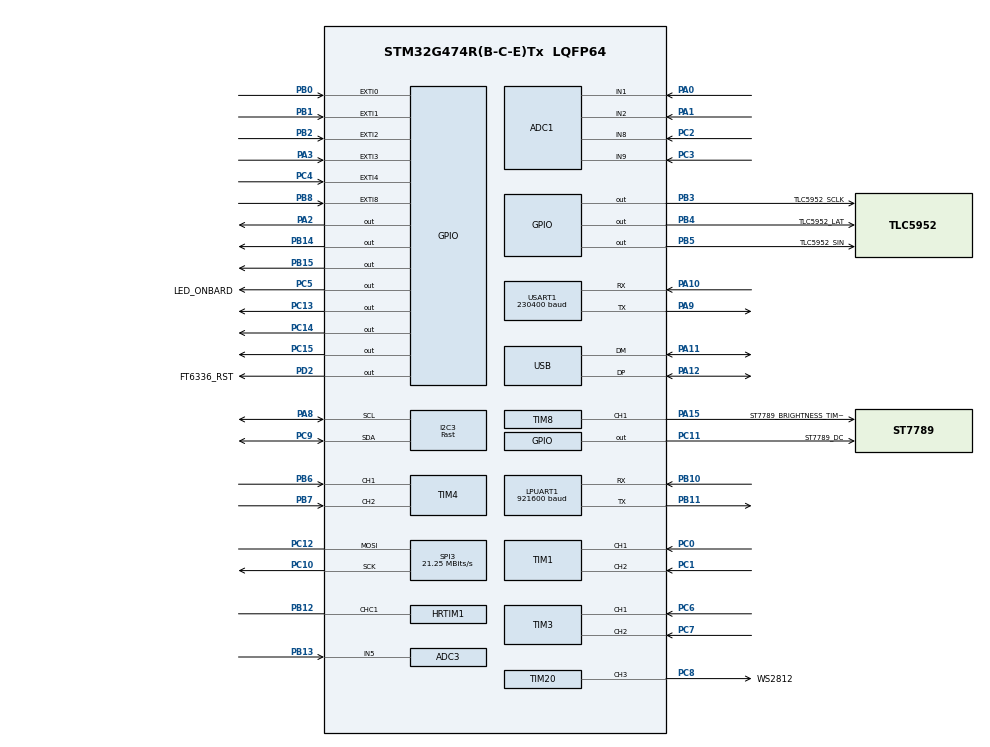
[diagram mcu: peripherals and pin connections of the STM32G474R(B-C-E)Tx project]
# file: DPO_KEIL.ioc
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ADC1.Channel-0\#ChannelRegularConversion=ADC_CHANNEL_8
ADC1.Channel-1\#ChannelRegularConversion=ADC_CHANNEL_9
ADC1.Channel-2\#ChannelRegularConversion=ADC_CHANNEL_1
ADC1.Channel-3\#ChannelRegularConversion=ADC_CHANNEL_2
ADC1.ClockPrescaler=ADC_CLOCK_ASYNC_DIV1
ADC1.ContinuousConvMode=ENABLE
ADC1.DMAContinuousRequests=ENABLE
ADC1.EOCSelection=ADC_EOC_SEQ_CONV
ADC1.ExternalTrigConv=ADC_EXTERNALTRIG_T6_TRGO
ADC1.NbrOfConversion=4
ADC1.NbrOfConversionFlag=1
ADC1.OffsetNumber-0\#ChannelRegularConversion=ADC_OFFSET_NONE
ADC1.OffsetNumber-1\#ChannelRegularConversion=ADC_OFFSET_NONE
ADC1.OffsetNumber-2\#ChannelRegularConversion=ADC_OFFSET_NONE
ADC1.OffsetNumber-3\#ChannelRegularConversion=ADC_OFFSET_NONE
ADC1.Rank-0\#ChannelRegularConversion=1
ADC1.Rank-1\#ChannelRegularConversion=2
ADC1.Rank-2\#ChannelRegularConversion=3
ADC1.Rank-3\#ChannelRegularConversion=4
ADC1.SamplingTime-0\#ChannelRegularConversion=ADC_SAMPLETIME_2CYCLES_5
ADC1.SamplingTime-1\#ChannelRegularConversion=ADC_SAMPLETIME_2CYCLES_5
ADC1.SamplingTime-2\#ChannelRegularConversion=ADC_SAMPLETIME_2CYCLES_5
ADC1.SamplingTime-3\#ChannelRegularConversion=ADC_SAMPLETIME_2CYCLES_5
ADC1.master=1
ADC3.Channel-0\#ChannelRegularConversion=ADC_CHANNEL_5
ADC3.ClockPrescaler=ADC_CLOCK_ASYNC_DIV1
ADC3.NbrOfConversionFlag=1
ADC3.OffsetNumber-0\#ChannelRegularConversion=ADC_OFFSET_NONE
ADC3.Rank-0\#ChannelRegularConversion=1
ADC3.SamplingTime-0\#ChannelRegularConversion=ADC_SAMPLETIME_2CYCLES_5
ADC3.master=1
Dma.ADC1.8.Direction=DMA_PERIPH_TO_MEMORY
Dma.ADC1.8.EventEnable=DISABLE
Dma.ADC1.8.Instance=DMA2_Channel1
Dma.ADC1.8.MemDataAlignment=DMA_MDATAALIGN_WORD
Dma.ADC1.8.MemInc=DMA_MINC_ENABLE
Dma.ADC1.8.Mode=DMA_CIRCULAR
Dma.ADC1.8.PeriphDataAlignment=DMA_PDATAALIGN_WORD
Dma.ADC1.8.PeriphInc=DMA_PINC_DISABLE
Dma.ADC1.8.Polarity=HAL_DMAMUX_REQ_GEN_RISING
Dma.ADC1.8.Priority=DMA_PRIORITY_LOW
Dma.ADC1.8.RequestNumber=1
Dma.ADC1.8.SignalID=NONE
Dma.ADC1.8.SyncEnable=DISABLE
Dma.ADC1.8.SyncPolarity=HAL_DMAMUX_SYNC_NO_EVENT
Dma.ADC1.8.SyncRequestNumber=1
Dma.ADC1.8.SyncSignalID=NONE
Dma.I2C3_RX.6.Direction=DMA_PERIPH_TO_MEMORY
Dma.I2C3_RX.6.EventEnable=DISABLE
Dma.I2C3_RX.6.Instance=DMA1_Channel7
Dma.I2C3_RX.6.MemDataAlignment=DMA_MDATAALIGN_BYTE
Dma.I2C3_RX.6.MemInc=DMA_MINC_ENABLE
Dma.I2C3_RX.6.Mode=DMA_NORMAL
Dma.I2C3_RX.6.PeriphDataAlignment=DMA_PDATAALIGN_BYTE
Dma.I2C3_RX.6.PeriphInc=DMA_PINC_DISABLE
Dma.I2C3_RX.6.Polarity=HAL_DMAMUX_REQ_GEN_RISING
Dma.I2C3_RX.6.Priority=DMA_PRIORITY_LOW
Dma.I2C3_RX.6.RequestNumber=1
Dma.I2C3_RX.6.SignalID=NONE
Dma.I2C3_RX.6.SyncEnable=DISABLE
Dma.I2C3_RX.6.SyncPolarity=HAL_DMAMUX_SYNC_NO_EVENT
Dma.I2C3_RX.6.SyncRequestNumber=1
Dma.I2C3_RX.6.SyncSignalID=NONE
Dma.I2C3_TX.5.Direction=DMA_MEMORY_TO_PERIPH
Dma.I2C3_TX.5.EventEnable=DISABLE
Dma.I2C3_TX.5.Instance=DMA1_Channel6
Dma.I2C3_TX.5.MemDataAlignment=DMA_MDATAALIGN_BYTE
Dma.I2C3_TX.5.MemInc=DMA_MINC_ENABLE
Dma.I2C3_TX.5.Mode=DMA_NORMAL
Dma.I2C3_TX.5.PeriphDataAlignment=DMA_PDATAALIGN_BYTE
Dma.I2C3_TX.5.PeriphInc=DMA_PINC_DISABLE
Dma.I2C3_TX.5.Polarity=HAL_DMAMUX_REQ_GEN_RISING
Dma.I2C3_TX.5.Priority=DMA_PRIORITY_LOW
Dma.I2C3_TX.5.RequestNumber=1
Dma.I2C3_TX.5.SignalID=NONE
Dma.I2C3_TX.5.SyncEnable=DISABLE
Dma.I2C3_TX.5.SyncPolarity=HAL_DMAMUX_SYNC_NO_EVENT
Dma.I2C3_TX.5.SyncRequestNumber=1
Dma.I2C3_TX.5.SyncSignalID=NONE
Dma.LPUART1_RX.3.Direction=DMA_PERIPH_TO_MEMORY
Dma.LPUART1_RX.3.EventEnable=DISABLE
Dma.LPUART1_RX.3.Instance=DMA1_Channel4
Dma.LPUART1_RX.3.MemDataAlignment=DMA_MDATAALIGN_BYTE
Dma.LPUART1_RX.3.MemInc=DMA_MINC_ENABLE
Dma.LPUART1_RX.3.Mode=DMA_NORMAL
Dma.LPUART1_RX.3.PeriphDataAlignment=DMA_PDATAALIGN_BYTE
Dma.LPUART1_RX.3.PeriphInc=DMA_PINC_DISABLE
Dma.LPUART1_RX.3.Polarity=HAL_DMAMUX_REQ_GEN_RISING
Dma.LPUART1_RX.3.Priority=DMA_PRIORITY_LOW
Dma.LPUART1_RX.3.RequestNumber=1
Dma.LPUART1_RX.3.SignalID=NONE
Dma.LPUART1_RX.3.SyncEnable=DISABLE
Dma.LPUART1_RX.3.SyncPolarity=HAL_DMAMUX_SYNC_NO_EVENT
Dma.LPUART1_RX.3.SyncRequestNumber=1
Dma.LPUART1_RX.3.SyncSignalID=NONE
Dma.LPUART1_TX.4.Direction=DMA_MEMORY_TO_PERIPH
Dma.LPUART1_TX.4.EventEnable=DISABLE
Dma.LPUART1_TX.4.Instance=DMA1_Channel5
Dma.LPUART1_TX.4.MemDataAlignment=DMA_MDATAALIGN_BYTE
Dma.LPUART1_TX.4.MemInc=DMA_MINC_ENABLE
Dma.LPUART1_TX.4.Mode=DMA_NORMAL
Dma.LPUART1_TX.4.PeriphDataAlignment=DMA_PDATAALIGN_BYTE
Dma.LPUART1_TX.4.PeriphInc=DMA_PINC_DISABLE
Dma.LPUART1_TX.4.Polarity=HAL_DMAMUX_REQ_GEN_RISING
Dma.LPUART1_TX.4.Priority=DMA_PRIORITY_LOW
Dma.LPUART1_TX.4.RequestNumber=1
Dma.LPUART1_TX.4.SignalID=NONE
Dma.LPUART1_TX.4.SyncEnable=DISABLE
Dma.LPUART1_TX.4.SyncPolarity=HAL_DMAMUX_SYNC_NO_EVENT
Dma.LPUART1_TX.4.SyncRequestNumber=1
Dma.LPUART1_TX.4.SyncSignalID=NONE
Dma.Request0=TIM20_CH3
Dma.Request1=USART1_RX
Dma.Request2=USART1_TX
Dma.Request3=LPUART1_RX
Dma.Request4=LPUART1_TX
Dma.Request5=I2C3_TX
Dma.Request6=I2C3_RX
Dma.Request7=SPI3_TX
Dma.Request8=ADC1
Dma.SPI3_TX.7.Direction=DMA_MEMORY_TO_PERIPH
Dma.SPI3_TX.7.EventEnable=DISABLE
Dma.SPI3_TX.7.Instance=DMA1_Channel8
Dma.SPI3_TX.7.MemDataAlignment=DMA_MDATAALIGN_BYTE
Dma.SPI3_TX.7.MemInc=DMA_MINC_ENABLE
Dma.SPI3_TX.7.Mode=DMA_NORMAL
Dma.SPI3_TX.7.PeriphDataAlignment=DMA_PDATAALIGN_BYTE
Dma.SPI3_TX.7.PeriphInc=DMA_PINC_DISABLE
Dma.SPI3_TX.7.Polarity=HAL_DMAMUX_REQ_GEN_RISING
Dma.SPI3_TX.7.Priority=DMA_PRIORITY_LOW
Dma.SPI3_TX.7.RequestNumber=1
Dma.SPI3_TX.7.SignalID=NONE
Dma.SPI3_TX.7.SyncEnable=DISABLE
Dma.SPI3_TX.7.SyncPolarity=HAL_DMAMUX_SYNC_NO_EVENT
Dma.SPI3_TX.7.SyncRequestNumber=1
Dma.SPI3_TX.7.SyncSignalID=NONE
Dma.TIM20_CH3.0.Direction=DMA_MEMORY_TO_PERIPH
Dma.TIM20_CH3.0.EventEnable=DISABLE
Dma.TIM20_CH3.0.Instance=DMA1_Channel1
Dma.TIM20_CH3.0.MemDataAlignment=DMA_MDATAALIGN_HALFWORD
Dma.TIM20_CH3.0.MemInc=DMA_MINC_ENABLE
Dma.TIM20_CH3.0.Mode=DMA_NORMAL
Dma.TIM20_CH3.0.PeriphDataAlignment=DMA_PDATAALIGN_HALFWORD
Dma.TIM20_CH3.0.PeriphInc=DMA_PINC_DISABLE
Dma.TIM20_CH3.0.Polarity=HAL_DMAMUX_REQ_GEN_RISING
Dma.TIM20_CH3.0.Priority=DMA_PRIORITY_LOW
Dma.TIM20_CH3.0.RequestNumber=1
Dma.TIM20_CH3.0.SignalID=NONE
Dma.TIM20_CH3.0.SyncEnable=DISABLE
Dma.TIM20_CH3.0.SyncPolarity=HAL_DMAMUX_SYNC_NO_EVENT
Dma.TIM20_CH3.0.SyncRequestNumber=1
Dma.TIM20_CH3.0.SyncSignalID=NONE
Dma.USART1_RX.1.Direction=DMA_PERIPH_TO_MEMORY
Dma.USART1_RX.1.EventEnable=DISABLE
Dma.USART1_RX.1.Instance=DMA1_Channel2
Dma.USART1_RX.1.MemDataAlignment=DMA_MDATAALIGN_BYTE
Dma.USART1_RX.1.MemInc=DMA_MINC_ENABLE
Dma.USART1_RX.1.Mode=DMA_NORMAL
Dma.USART1_RX.1.PeriphDataAlignment=DMA_PDATAALIGN_BYTE
Dma.USART1_RX.1.PeriphInc=DMA_PINC_DISABLE
Dma.USART1_RX.1.Polarity=HAL_DMAMUX_REQ_GEN_RISING
Dma.USART1_RX.1.Priority=DMA_PRIORITY_LOW
Dma.USART1_RX.1.RequestNumber=1
Dma.USART1_RX.1.SignalID=NONE
Dma.USART1_RX.1.SyncEnable=DISABLE
Dma.USART1_RX.1.SyncPolarity=HAL_DMAMUX_SYNC_NO_EVENT
Dma.USART1_RX.1.SyncRequestNumber=1
Dma.USART1_RX.1.SyncSignalID=NONE
Dma.USART1_TX.2.Direction=DMA_MEMORY_TO_PERIPH
Dma.USART1_TX.2.EventEnable=DISABLE
Dma.USART1_TX.2.Instance=DMA1_Channel3
Dma.USART1_TX.2.MemDataAlignment=DMA_MDATAALIGN_BYTE
Dma.USART1_TX.2.MemInc=DMA_MINC_ENABLE
Dma.USART1_TX.2.Mode=DMA_NORMAL
Dma.USART1_TX.2.PeriphDataAlignment=DMA_PDATAALIGN_BYTE
Dma.USART1_TX.2.PeriphInc=DMA_PINC_DISABLE
Dma.USART1_TX.2.Polarity=HAL_DMAMUX_REQ_GEN_RISING
Dma.USART1_TX.2.Priority=DMA_PRIORITY_LOW
Dma.USART1_TX.2.RequestNumber=1
Dma.USART1_TX.2.SignalID=NONE
Dma.USART1_TX.2.SyncEnable=DISABLE
Dma.USART1_TX.2.SyncPolarity=HAL_DMAMUX_SYNC_NO_EVENT
Dma.USART1_TX.2.SyncRequestNumber=1
Dma.USART1_TX.2.SyncSignalID=NONE
HRTIM1.Configuration_TC=Simple
HRTIM1.PWMChannel_TC1=HRTIM_OUTPUT_TC1
HRTIM1.PWMPulse_TC1=0x30
HRTIM1.Periode_TC=0x60
HRTIM1.RepetitionCounter-Output_TC1=0
I2C3.I2C_Speed_Mode=I2C_Fast
I2C3.Timing=0x40621236
LPUART1.BaudRate=921600
Mcu.Family=STM32G4
Mcu.Name=STM32G474R(B-C-E)Tx
Mcu.Package=LQFP64
NVIC.DMA1_Channel1_IRQn=true\:0\:0\:false\:false\:true\:false\:true\:true
NVIC.DMA1_Channel2_IRQn=true\:0\:0\:false\:false\:true\:false\:true\:true
NVIC.DMA1_Channel3_IRQn=true\:0\:0\:false\:false\:true\:false\:true\:true
NVIC.DMA1_Channel4_IRQn=true\:0\:0\:false\:false\:true\:false\:true\:true
NVIC.DMA1_Channel5_IRQn=true\:0\:0\:false\:false\:true\:false\:true\:true
NVIC.DMA1_Channel6_IRQn=true\:0\:0\:false\:false\:true\:false\:true\:true
NVIC.DMA1_Channel7_IRQn=true\:0\:0\:false\:false\:true\:false\:true\:true
NVIC.DMA1_Channel8_IRQn=true\:0\:0\:false\:false\:true\:false\:true\:true
NVIC.DMA2_Channel1_IRQn=true\:0\:0\:false\:false\:true\:false\:true\:true
NVIC.LPUART1_IRQn=true\:0\:0\:false\:false\:true\:true\:true\:true
NVIC.PriorityGroup=NVIC_PRIORITYGROUP_4
NVIC.USART1_IRQn=true\:0\:0\:false\:false\:true\:true\:true\:true
NVIC.USB_LP_IRQn=true\:0\:0\:false\:false\:true\:false\:true\:true
PA0.Mode=IN1-Single-Ended
PA0.Signal=ADC1_IN1
PA1.Mode=IN2-Single-Ended
PA1.Signal=ADC1_IN2
PA10.Mode=Asynchronous
PA10.Signal=USART1_RX
PA11.Mode=Device
PA11.Signal=USB_DM
PA12.Mode=Device
PA12.Signal=USB_DP
PA13.Mode=Serial_Wire
PA13.Signal=SYS_JTMS-SWDIO
PA14.Mode=Serial_Wire
PA14.Signal=SYS_JTCK-SWCLK
PA15.GPIO_Label=ST7789_BRIGHTNESS_TIM8_1
PA15.Signal=S_TIM8_CH1
PA2.Signal=GPIO_Output
PA3.Signal=GPXTI3
PA4.Signal=COMP_DAC11_group
PA5.Signal=COMP_DAC12_group
PA6.Signal=COMP_DAC21_group
PA7.Signal=ADC2_IN4
PA8.Mode=I2C
PA8.Signal=I2C3_SCL
PA9.Mode=Asynchronous
PA9.Signal=USART1_TX
PB0.Signal=GPXTI0
PB1.Signal=GPXTI1
PB10.Mode=Asynchronous
PB10.Signal=LPUART1_RX
PB11.Mode=Asynchronous
PB11.Signal=LPUART1_TX
PB12.Mode=Output_TC1
PB12.Signal=HRTIM1_CHC1
PB13.Mode=IN5-Single-Ended
PB13.Signal=ADC3_IN5
PB14.Signal=GPIO_Output
PB15.Signal=GPIO_Output
PB2.Signal=GPXTI2
PB3.GPIO_Label=TLC5952_SCLK
PB3.Signal=GPIO_Output
PB4.GPIO_Label=TLC5952_LAT
PB4.Signal=GPIO_Output
PB5.GPIO_Label=TLC5952_SIN
PB5.Signal=GPIO_Output
PB6.Signal=S_TIM4_CH1
PB7.Signal=S_TIM4_CH2
PB8-BOOT0.Signal=GPXTI8
PB9.GPIO_Label=BEEP_TIM8_3
PB9.Signal=S_TIM8_CH3
PC0.Signal=S_TIM1_CH1
PC1.Signal=S_TIM1_CH2
PC10.Mode=Simplex_Bidirectional_Master
PC10.Signal=SPI3_SCK
PC11.GPIO_Label=ST7789_DC
PC11.Signal=GPIO_Output
PC12.Mode=Simplex_Bidirectional_Master
PC12.Signal=SPI3_MOSI
PC13.Signal=GPIO_Output
PC14-OSC32_IN.Signal=GPIO_Output
PC15-OSC32_OUT.Signal=GPIO_Output
PC2.Mode=IN8-Single-Ended
PC2.Signal=ADC1_IN8
PC3.Mode=IN9-Single-Ended
PC3.Signal=ADC1_IN9
PC4.Signal=GPXTI4
PC5.GPIO_Label=LED_ONBARD
PC5.Signal=GPIO_Output
PC6.Signal=S_TIM3_CH1
PC7.Signal=S_TIM3_CH2
PC8.GPIO_Label=WS2812
PC8.Signal=S_TIM20_CH3
PC9.Mode=I2C
PC9.Signal=I2C3_SDA
PD2.GPIO_Label=FT6336_RST
PD2.Signal=GPIO_Output
PF0-OSC_IN.Mode=HSE-External-Oscillator
PF0-OSC_IN.Signal=RCC_OSC_IN
PF1-OSC_OUT.Mode=HSE-External-Oscillator
PF1-OSC_OUT.Signal=RCC_OSC_OUT
ProjectManager.HeapSize=0x200
ProjectManager.StackSize=0x400
ProjectManager.TargetToolchain=MDK-ARM V5.32
RCC.ADC12CLockSelection=RCC_ADC12CLKSOURCE_PLL
RCC.ADC12Freq_Value=56666666.666666664
RCC.ADC345CLockSelection=RCC_ADC345CLKSOURCE_PLL
RCC.ADC345Freq_Value=56666666.666666664
RCC.AHBFreq_Value=170000000
RCC.APB1Freq_Value=170000000
RCC.APB1TimFreq_Value=170000000
RCC.APB2Freq_Value=170000000
RCC.APB2TimFreq_Value=170000000
RCC.CK48CLockSelection=RCC_USBCLKSOURCE_HSI48
RCC.CortexFreq_Value=170000000
RCC.EXTERNAL_CLOCK_VALUE=12288000
RCC.HCLKFreq_Value=170000000
RCC.HSE_VALUE=16000000
RCC.HSI48_VALUE=48000000
RCC.HSI_VALUE=16000000
RCC.LSE_VALUE=32768
RCC.PLLM=RCC_PLLM_DIV4
RCC.PLLN=85
RCC.PLLP=RCC_PLLP_DIV6
RCC.PLLSourceVirtual=RCC_PLLSOURCE_HSE
RCC.SYSCLKFreq_VALUE=170000000
RCC.SYSCLKSource=RCC_SYSCLKSOURCE_PLLCLK
RCC.USBFreq_Value=48000000
RCC.VCOOutputFreq_Value=340000000
SH.COMP_DAC11_group.0=DAC1_OUT1
SH.COMP_DAC12_group.0=DAC1_OUT2
SH.COMP_DAC21_group.0=DAC2_OUT1
SH.S_TIM1_CH1.0=TIM1_CH1,Encoder_Interface
SH.S_TIM1_CH2.0=TIM1_CH2,Encoder_Interface
SH.S_TIM20_CH3.0=TIM20_CH3,PWM Generation3 CH3
SH.S_TIM3_CH1.0=TIM3_CH1,Encoder_Interface
SH.S_TIM3_CH2.0=TIM3_CH2,Encoder_Interface
SH.S_TIM4_CH1.0=TIM4_CH1,Encoder_Interface
SH.S_TIM4_CH2.0=TIM4_CH2,Encoder_Interface
SH.S_TIM8_CH1.0=TIM8_CH1,PWM Generation1 CH1
SH.S_TIM8_CH3.0=TIM8_CH3
SPI3.BaudRatePrescaler=SPI_BAUDRATEPRESCALER_8
SPI3.CLKPolarity=SPI_POLARITY_HIGH
SPI3.CalculateBaudRate=21.25 MBits/s
SPI3.DataSize=SPI_DATASIZE_8BIT
SPI3.Direction=SPI_DIRECTION_1LINE
SPI3.Mode=SPI_MODE_MASTER
SPI3.VirtualType=VM_MASTER
TIM20.Channel-PWM\ Generation3\ CH3=TIM_CHANNEL_3
TIM20.PeriodNoDither=180-1
TIM6.PeriodNoDither=180
TIM6.TIM_MasterOutputTrigger=TIM_TRGO_UPDATE
TIM8.Channel-PWM\ Generation1\ CH1=TIM_CHANNEL_1
TIM8.PeriodNoDither=1000-1
TIM8.Prescaler=180-1
TIM8.PulseNoDither_1=500
USART1.BaudRate=230400
USART1.VirtualMode-Asynchronous=VM_ASYNC
USB_DEVICE.CLASS_NAME_FS=CDC
USB_DEVICE.VirtualMode=Cdc
USB_DEVICE.VirtualModeFS=Cdc_FS
VP_SYS_VS_DBSignals.Mode=DisableDeadBatterySignals
VP_TIM6_VS_ClockSourceINT.Mode=Enable_Timer
VP_TIM8_VS_ClockSourceINT.Mode=Internal
VP_USB_DEVICE_VS_USB_DEVICE_CDC_FS.Mode=CDC_FS
board=custom

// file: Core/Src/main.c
/* USER CODE BEGIN Header */
/**
  ******************************************************************************
  * @file           : main.c
  * @brief          : Main program body
  ******************************************************************************
  * @attention
  *
  * Copyright (c) 2025 STMicroelectronics.
  * All rights reserved.
  *
  * This software is licensed under terms that can be found in the LICENSE file
  * in the root directory of this software component.
  * If no LICENSE file comes with this software, it is provided AS-IS.
  *
  ******************************************************************************
  */
/* USER CODE END Header */
#include "main.h"
#include "usb_device.h"

/* USER CODE BEGIN Includes */

#include "usbd_cdc_if.h"

#include "MyLib.h"

#include "ft6336.h"

#include "st7789.h"

#include "TLC5952.h"

#include "ws2812.h"

#include "aht20.h"

#include "Views.h"

#include "mpu6050.h"

/* USER CODE END Includes */

ADC_HandleTypeDef hadc1;
ADC_HandleTypeDef hadc3;
DMA_HandleTypeDef hdma_adc1;

HRTIM_HandleTypeDef hhrtim1;

I2C_HandleTypeDef hi2c3;
DMA_HandleTypeDef hdma_i2c3_tx;
DMA_HandleTypeDef hdma_i2c3_rx;

UART_HandleTypeDef hlpuart1;
UART_HandleTypeDef huart1;
DMA_HandleTypeDef hdma_lpuart1_rx;
DMA_HandleTypeDef hdma_lpuart1_tx;
DMA_HandleTypeDef hdma_usart1_rx;
DMA_HandleTypeDef hdma_usart1_tx;

SPI_HandleTypeDef hspi3;
DMA_HandleTypeDef hdma_spi3_tx;

TIM_HandleTypeDef htim1;
TIM_HandleTypeDef htim3;
TIM_HandleTypeDef htim4;
TIM_HandleTypeDef htim6;
TIM_HandleTypeDef htim8;
TIM_HandleTypeDef htim20;
DMA_HandleTypeDef hdma_tim20_ch3;

/* USER CODE BEGIN PV */
uint8_t BLE_rx_data[256] = {0};

MPU6050_t data_mpu6050={0};

float Temperature,Humidity=0;

uint32_t CMP_SET= 0x30;

/* USER CODE END PV */

void SystemClock_Config(void);
static void MX_GPIO_Init(void);
static void MX_DMA_Init(void);
static void MX_ADC1_Init(void);
static void MX_ADC3_Init(void);
static void MX_LPUART1_UART_Init(void);
static void MX_SPI3_Init(void);
static void MX_I2C3_Init(void);
static void MX_TIM1_Init(void);
static void MX_TIM3_Init(void);
static void MX_TIM4_Init(void);
static void MX_TIM20_Init(void);
static void MX_TIM8_Init(void);
static void MX_USART1_UART_Init(void);
static void MX_TIM6_Init(void);
static void MX_HRTIM1_Init(void);

/* USER CODE BEGIN 0 */

uint32_t BUFFER_ADC1[4096]={0};
uint32_t BUFFER_ADC1_proc[4096]={0};

uint8_t LOCK_CH1 = 0;

char BUFFER_CDC[500]="hello world\r\n";

// 彩虹颜色配置
RGBColor rainbow_colors[WS2812_NUM] = {
    {255,   0,   0},
    {255, 115,   0},
    {255, 201,   0},
    {229, 242,   0},
    { 51, 153,   0},
    {  0,  64, 127},
    { 14,   0, 230},
    { 67,   0, 142},
    {172,  77, 194},
    {243,  91, 166}
};

/* USER CODE END 0 */

int main(void)
{

  /* MCU Configuration--------------------------------------------------------*/

  /* Reset of all peripherals, Initializes the Flash interface and the Systick. */
  HAL_Init();

  /* Configure the system clock */
  SystemClock_Config();

  /* Initialize all configured peripherals */
  MX_GPIO_Init();
  MX_DMA_Init();
  MX_ADC1_Init();
  MX_ADC3_Init();
  MX_LPUART1_UART_Init();
  MX_SPI3_Init();
  MX_I2C3_Init();
  MX_TIM1_Init();
  MX_TIM3_Init();
  MX_TIM4_Init();
  MX_TIM20_Init();
  MX_TIM8_Init();
  MX_USART1_UART_Init();
  MX_USB_Device_Init();
  MX_TIM6_Init();
  MX_HRTIM1_Init();
  /* USER CODE BEGIN 2 */

  htim1.Instance->CNT=32767;
  htim3.Instance->CNT=32767;
  htim4.Instance->CNT=32767;

  HAL_ADC_Start_DMA(&hadc1,BUFFER_ADC1,4096);

  HAL_TIM_Base_Start(&htim6);

  HAL_TIM_Encoder_Start(&htim1, TIM_CHANNEL_ALL);
  HAL_TIM_Encoder_Start(&htim3, TIM_CHANNEL_ALL);
  HAL_TIM_Encoder_Start(&htim4, TIM_CHANNEL_ALL);

  HAL_TIM_PWM_Start(&htim8, TIM_CHANNEL_1);

  MPU6050_Init();

  ST7789_Init();
  View_DoubaoWelcome();

  AHT20_Init();

  TLC5952_Init();

  // WS2812_Set_All(0xcc66ff);
  // WS2812_Set_All(0x001000);
  // WS2812_Update();

  HAL_HRTIM_SimplePWMStart(&hhrtim1,HRTIM_TIMERINDEX_TIMER_C,HRTIM_OUTPUT_TC1);

  HAL_UARTEx_ReceiveToIdle_DMA(&huart1, BLE_rx_data, sizeof(BLE_rx_data));
  __HAL_DMA_DISABLE_IT(huart1.hdmarx, DMA_IT_HT);

  WS2812_Write_Colors(rainbow_colors,10);

  /* USER CODE END 2 */

  /* Infinite loop */
  /* USER CODE BEGIN WHILE */
  while (1)
  {

		// printf("123\r");
    // HAL_UART_Transmit(&hlpuart1,(uint8_t*)BUFFER_CDC , strlen(BUFFER_CDC), HAL_MAX_DELAY);

  if (LOCK_CH1)
  {

    for (uint32_t i = 0; i < 1024; i++)
    {
      sprintf(BUFFER_CDC,"ADC: %d,%d,%d,%d\r\n",BUFFER_ADC1_proc[i*4],BUFFER_ADC1_proc[i*4+1],BUFFER_ADC1_proc[i*4+2],BUFFER_ADC1_proc[i*4+3]);
      CDC_Transmit_FS((uint8_t*)BUFFER_CDC,strlen(BUFFER_CDC));
    }

    LOCK_CH1 = 0;
  }

    MPU6050_Read_All(&data_mpu6050);

    // sprintf(BUFFER_CDC,"ADC1: %f,%f\r\n",data_mpu6050.KalmanAngleX,data_mpu6050.KalmanAngleY);//加速度计

    // CDC_Transmit_FS((uint8_t*)BUFFER_CDC,strlen(BUFFER_CDC));

    HAL_GPIO_WritePin(LED_ONBARD_GPIO_Port, LED_ONBARD_Pin, 1);
    // HAL_Delay(100);
    AHT20_Read(&Temperature,&Humidity);
    HAL_GPIO_WritePin(LED_ONBARD_GPIO_Port, LED_ONBARD_Pin, 0);
    // HAL_Delay(100);

		TLC5952_WriteLED();
		TLC5952_WriteControl();

    // HRTIM1->sTimerxRegs[HRTIM_TIMERINDEX_TIMER_C].CMP1xR = CMP_SET;

    __HAL_HRTIM_SETCOMPARE(&hhrtim1, HRTIM_TIMERINDEX_TIMER_C, HRTIM_COMPAREUNIT_1, CMP_SET);

    HAL_HRTIM_SoftwareUpdate(&hhrtim1, HRTIM_TIMERUPDATE_C);

    /* USER CODE END WHILE */

  }
}

void SystemClock_Config(void)
{
  RCC_OscInitTypeDef RCC_OscInitStruct = {0};
  RCC_ClkInitTypeDef RCC_ClkInitStruct = {0};

  /** Configure the main internal regulator output voltage
  */
  HAL_PWREx_ControlVoltageScaling(PWR_REGULATOR_VOLTAGE_SCALE1_BOOST);

  /** Initializes the RCC Oscillators according to the specified parameters
  * in the RCC_OscInitTypeDef structure.
  */
  RCC_OscInitStruct.OscillatorType = RCC_OSCILLATORTYPE_HSI48|RCC_OSCILLATORTYPE_HSE;
  RCC_OscInitStruct.HSEState = RCC_HSE_ON;
  RCC_OscInitStruct.HSI48State = RCC_HSI48_ON;
  RCC_OscInitStruct.PLL.PLLState = RCC_PLL_ON;
  RCC_OscInitStruct.PLL.PLLSource = RCC_PLLSOURCE_HSE;
  RCC_OscInitStruct.PLL.PLLM = RCC_PLLM_DIV4;
  RCC_OscInitStruct.PLL.PLLN = 90;
  RCC_OscInitStruct.PLL.PLLP = RCC_PLLP_DIV6;
  RCC_OscInitStruct.PLL.PLLQ = RCC_PLLQ_DIV2;
  RCC_OscInitStruct.PLL.PLLR = RCC_PLLR_DIV2;
  if (HAL_RCC_OscConfig(&RCC_OscInitStruct) != HAL_OK)
  {
    Error_Handler();
  }

  /** Initializes the CPU, AHB and APB buses clocks
  */
  RCC_ClkInitStruct.ClockType = RCC_CLOCKTYPE_HCLK|RCC_CLOCKTYPE_SYSCLK
                              |RCC_CLOCKTYPE_PCLK1|RCC_CLOCKTYPE_PCLK2;
  RCC_ClkInitStruct.SYSCLKSource = RCC_SYSCLKSOURCE_PLLCLK;
  RCC_ClkInitStruct.AHBCLKDivider = RCC_SYSCLK_DIV1;
  RCC_ClkInitStruct.APB1CLKDivider = RCC_HCLK_DIV1;
  RCC_ClkInitStruct.APB2CLKDivider = RCC_HCLK_DIV1;

  if (HAL_RCC_ClockConfig(&RCC_ClkInitStruct, FLASH_LATENCY_4) != HAL_OK)
  {
    Error_Handler();
  }
}

static void MX_ADC1_Init(void)
{

  ADC_MultiModeTypeDef multimode = {0};
  ADC_ChannelConfTypeDef sConfig = {0};

  /** Common config
  */
  hadc1.Instance = ADC1;
  hadc1.Init.ClockPrescaler = ADC_CLOCK_ASYNC_DIV1;
  hadc1.Init.Resolution = ADC_RESOLUTION_12B;
  hadc1.Init.DataAlign = ADC_DATAALIGN_RIGHT;
  hadc1.Init.GainCompensation = 0;
  hadc1.Init.ScanConvMode = ADC_SCAN_ENABLE;
  hadc1.Init.EOCSelection = ADC_EOC_SEQ_CONV;
  hadc1.Init.LowPowerAutoWait = DISABLE;
  hadc1.Init.ContinuousConvMode = ENABLE;
  hadc1.Init.NbrOfConversion = 4;
  hadc1.Init.DiscontinuousConvMode = DISABLE;
  hadc1.Init.ExternalTrigConv = ADC_EXTERNALTRIG_T6_TRGO;
  hadc1.Init.ExternalTrigConvEdge = ADC_EXTERNALTRIGCONVEDGE_RISING;
  hadc1.Init.DMAContinuousRequests = ENABLE;
  hadc1.Init.Overrun = ADC_OVR_DATA_PRESERVED;
  hadc1.Init.OversamplingMode = DISABLE;
  if (HAL_ADC_Init(&hadc1) != HAL_OK)
  {
    Error_Handler();
  }

  /** Configure the ADC multi-mode
  */
  multimode.Mode = ADC_MODE_INDEPENDENT;
  if (HAL_ADCEx_MultiModeConfigChannel(&hadc1, &multimode) != HAL_OK)
  {
    Error_Handler();
  }

  /** Configure Regular Channel
  */
  sConfig.Channel = ADC_CHANNEL_8;
  sConfig.Rank = ADC_REGULAR_RANK_1;
  sConfig.SamplingTime = ADC_SAMPLETIME_2CYCLES_5;
  sConfig.SingleDiff = ADC_SINGLE_ENDED;
  sConfig.OffsetNumber = ADC_OFFSET_NONE;
  sConfig.Offset = 0;
  if (HAL_ADC_ConfigChannel(&hadc1, &sConfig) != HAL_OK)
  {
    Error_Handler();
  }

  /** Configure Regular Channel
  */
  sConfig.Channel = ADC_CHANNEL_9;
  sConfig.Rank = ADC_REGULAR_RANK_2;
  if (HAL_ADC_ConfigChannel(&hadc1, &sConfig) != HAL_OK)
  {
    Error_Handler();
  }

  /** Configure Regular Channel
  */
  sConfig.Channel = ADC_CHANNEL_1;
  sConfig.Rank = ADC_REGULAR_RANK_3;
  if (HAL_ADC_ConfigChannel(&hadc1, &sConfig) != HAL_OK)
  {
    Error_Handler();
  }

  /** Configure Regular Channel
  */
  sConfig.Channel = ADC_CHANNEL_2;
  sConfig.Rank = ADC_REGULAR_RANK_4;
  if (HAL_ADC_ConfigChannel(&hadc1, &sConfig) != HAL_OK)
  {
    Error_Handler();
  }

}

static void MX_ADC3_Init(void)
{

  ADC_MultiModeTypeDef multimode = {0};
  ADC_ChannelConfTypeDef sConfig = {0};

  /** Common config
  */
  hadc3.Instance = ADC3;
  hadc3.Init.ClockPrescaler = ADC_CLOCK_ASYNC_DIV1;
  hadc3.Init.Resolution = ADC_RESOLUTION_12B;
  hadc3.Init.DataAlign = ADC_DATAALIGN_RIGHT;
  hadc3.Init.GainCompensation = 0;
  hadc3.Init.ScanConvMode = ADC_SCAN_DISABLE;
  hadc3.Init.EOCSelection = ADC_EOC_SINGLE_CONV;
  hadc3.Init.LowPowerAutoWait = DISABLE;
  hadc3.Init.ContinuousConvMode = DISABLE;
  hadc3.Init.NbrOfConversion = 1;
  hadc3.Init.DiscontinuousConvMode = DISABLE;
  hadc3.Init.ExternalTrigConv = ADC_SOFTWARE_START;
  hadc3.Init.ExternalTrigConvEdge = ADC_EXTERNALTRIGCONVEDGE_NONE;
  hadc3.Init.DMAContinuousRequests = DISABLE;
  hadc3.Init.Overrun = ADC_OVR_DATA_PRESERVED;
  hadc3.Init.OversamplingMode = DISABLE;
  if (HAL_ADC_Init(&hadc3) != HAL_OK)
  {
    Error_Handler();
  }

  /** Configure the ADC multi-mode
  */
  multimode.Mode = ADC_MODE_INDEPENDENT;
  if (HAL_ADCEx_MultiModeConfigChannel(&hadc3, &multimode) != HAL_OK)
  {
    Error_Handler();
  }

  /** Configure Regular Channel
  */
  sConfig.Channel = ADC_CHANNEL_5;
  sConfig.Rank = ADC_REGULAR_RANK_1;
  sConfig.SamplingTime = ADC_SAMPLETIME_2CYCLES_5;
  sConfig.SingleDiff = ADC_SINGLE_ENDED;
  sConfig.OffsetNumber = ADC_OFFSET_NONE;
  sConfig.Offset = 0;
  if (HAL_ADC_ConfigChannel(&hadc3, &sConfig) != HAL_OK)
  {
    Error_Handler();
  }

}

static void MX_HRTIM1_Init(void)
{

  HRTIM_TimeBaseCfgTypeDef pTimeBaseCfg = {0};
  HRTIM_TimerCtlTypeDef pTimerCtl = {0};
  HRTIM_SimplePWMChannelCfgTypeDef pSimplePWMChannelCfg = {0};

  hhrtim1.Instance = HRTIM1;
  hhrtim1.Init.HRTIMInterruptResquests = HRTIM_IT_NONE;
  hhrtim1.Init.SyncOptions = HRTIM_SYNCOPTION_NONE;
  if (HAL_HRTIM_Init(&hhrtim1) != HAL_OK)
  {
    Error_Handler();
  }
  if (HAL_HRTIM_DLLCalibrationStart(&hhrtim1, HRTIM_CALIBRATIONRATE_3) != HAL_OK)
  {
    Error_Handler();
  }
  if (HAL_HRTIM_PollForDLLCalibration(&hhrtim1, 10) != HAL_OK)
  {
    Error_Handler();
  }
  pTimeBaseCfg.Period = 0x60;
  pTimeBaseCfg.RepetitionCounter = 0;
  pTimeBaseCfg.PrescalerRatio = HRTIM_PRESCALERRATIO_MUL32;
  pTimeBaseCfg.Mode = HRTIM_MODE_CONTINUOUS;
  if (HAL_HRTIM_TimeBaseConfig(&hhrtim1, HRTIM_TIMERINDEX_TIMER_C, &pTimeBaseCfg) != HAL_OK)
  {
    Error_Handler();
  }
  pTimerCtl.UpDownMode = HRTIM_TIMERUPDOWNMODE_UP;
  pTimerCtl.DualChannelDacEnable = HRTIM_TIMER_DCDE_DISABLED;

  if (HAL_HRTIM_WaveformTimerControl(&hhrtim1, HRTIM_TIMERINDEX_TIMER_C, &pTimerCtl) != HAL_OK)
  {
    Error_Handler();
  }
  pSimplePWMChannelCfg.Pulse = 0x30;
  pSimplePWMChannelCfg.Polarity = HRTIM_OUTPUTPOLARITY_HIGH;
  pSimplePWMChannelCfg.IdleLevel = HRTIM_OUTPUTIDLELEVEL_INACTIVE;
  if (HAL_HRTIM_SimplePWMChannelConfig(&hhrtim1, HRTIM_TIMERINDEX_TIMER_C, HRTIM_OUTPUT_TC1, &pSimplePWMChannelCfg) != HAL_OK)
  {
    Error_Handler();
  }
  HAL_HRTIM_MspPostInit(&hhrtim1);

}

static void MX_I2C3_Init(void)
{

  hi2c3.Instance = I2C3;
  hi2c3.Init.Timing = 0x40621236;
  hi2c3.Init.OwnAddress1 = 0;
  hi2c3.Init.AddressingMode = I2C_ADDRESSINGMODE_7BIT;
  hi2c3.Init.DualAddressMode = I2C_DUALADDRESS_DISABLE;
  hi2c3.Init.OwnAddress2 = 0;
  hi2c3.Init.OwnAddress2Masks = I2C_OA2_NOMASK;
  hi2c3.Init.GeneralCallMode = I2C_GENERALCALL_DISABLE;
  hi2c3.Init.NoStretchMode = I2C_NOSTRETCH_DISABLE;
  if (HAL_I2C_Init(&hi2c3) != HAL_OK)
  {
    Error_Handler();
  }

  /** Configure Analogue filter
  */
  if (HAL_I2CEx_ConfigAnalogFilter(&hi2c3, I2C_ANALOGFILTER_ENABLE) != HAL_OK)
  {
    Error_Handler();
  }

  /** Configure Digital filter
  */
  if (HAL_I2CEx_ConfigDigitalFilter(&hi2c3, 0) != HAL_OK)
  {
    Error_Handler();
  }

}

static void MX_LPUART1_UART_Init(void)
{

  hlpuart1.Instance = LPUART1;
  hlpuart1.Init.BaudRate = 921600;
  hlpuart1.Init.WordLength = UART_WORDLENGTH_8B;
  hlpuart1.Init.StopBits = UART_STOPBITS_1;
  hlpuart1.Init.Parity = UART_PARITY_NONE;
  hlpuart1.Init.Mode = UART_MODE_TX_RX;
  hlpuart1.Init.HwFlowCtl = UART_HWCONTROL_NONE;
  hlpuart1.Init.OneBitSampling = UART_ONE_BIT_SAMPLE_DISABLE;
  hlpuart1.Init.ClockPrescaler = UART_PRESCALER_DIV1;
  hlpuart1.AdvancedInit.AdvFeatureInit = UART_ADVFEATURE_NO_INIT;
  if (HAL_UART_Init(&hlpuart1) != HAL_OK)
  {
    Error_Handler();
  }
  if (HAL_UARTEx_SetTxFifoThreshold(&hlpuart1, UART_TXFIFO_THRESHOLD_1_8) != HAL_OK)
  {
    Error_Handler();
  }
  if (HAL_UARTEx_SetRxFifoThreshold(&hlpuart1, UART_RXFIFO_THRESHOLD_1_8) != HAL_OK)
  {
    Error_Handler();
  }
  if (HAL_UARTEx_DisableFifoMode(&hlpuart1) != HAL_OK)
  {
    Error_Handler();
  }

}

static void MX_USART1_UART_Init(void)
{

  huart1.Instance = USART1;
  huart1.Init.BaudRate = 230400;
  huart1.Init.WordLength = UART_WORDLENGTH_8B;
  huart1.Init.StopBits = UART_STOPBITS_1;
  huart1.Init.Parity = UART_PARITY_NONE;
  huart1.Init.Mode = UART_MODE_TX_RX;
  huart1.Init.HwFlowCtl = UART_HWCONTROL_NONE;
  huart1.Init.OverSampling = UART_OVERSAMPLING_16;
  huart1.Init.OneBitSampling = UART_ONE_BIT_SAMPLE_DISABLE;
  huart1.Init.ClockPrescaler = UART_PRESCALER_DIV1;
  huart1.AdvancedInit.AdvFeatureInit = UART_ADVFEATURE_NO_INIT;
  if (HAL_UART_Init(&huart1) != HAL_OK)
  {
    Error_Handler();
  }
  if (HAL_UARTEx_SetTxFifoThreshold(&huart1, UART_TXFIFO_THRESHOLD_1_8) != HAL_OK)
  {
    Error_Handler();
  }
  if (HAL_UARTEx_SetRxFifoThreshold(&huart1, UART_RXFIFO_THRESHOLD_1_8) != HAL_OK)
  {
    Error_Handler();
  }
  if (HAL_UARTEx_DisableFifoMode(&huart1) != HAL_OK)
  {
    Error_Handler();
  }

}

static void MX_SPI3_Init(void)
{

  /* SPI3 parameter configuration*/
  hspi3.Instance = SPI3;
  hspi3.Init.Mode = SPI_MODE_MASTER;
  hspi3.Init.Direction = SPI_DIRECTION_1LINE;
  hspi3.Init.DataSize = SPI_DATASIZE_8BIT;
  hspi3.Init.CLKPolarity = SPI_POLARITY_HIGH;
  hspi3.Init.CLKPhase = SPI_PHASE_1EDGE;
  hspi3.Init.NSS = SPI_NSS_SOFT;
  hspi3.Init.BaudRatePrescaler = SPI_BAUDRATEPRESCALER_8;
  hspi3.Init.FirstBit = SPI_FIRSTBIT_MSB;
  hspi3.Init.TIMode = SPI_TIMODE_DISABLE;
  hspi3.Init.CRCCalculation = SPI_CRCCALCULATION_DISABLE;
  hspi3.Init.CRCPolynomial = 7;
  hspi3.Init.CRCLength = SPI_CRC_LENGTH_DATASIZE;
  hspi3.Init.NSSPMode = SPI_NSS_PULSE_ENABLE;
  if (HAL_SPI_Init(&hspi3) != HAL_OK)
  {
    Error_Handler();
  }

}

static void MX_TIM1_Init(void)
{

  TIM_Encoder_InitTypeDef sConfig = {0};
  TIM_MasterConfigTypeDef sMasterConfig = {0};

  htim1.Instance = TIM1;
  htim1.Init.Prescaler = 0;
  htim1.Init.CounterMode = TIM_COUNTERMODE_UP;
  htim1.Init.Period = 65535;
  htim1.Init.ClockDivision = TIM_CLOCKDIVISION_DIV1;
  htim1.Init.RepetitionCounter = 0;
  htim1.Init.AutoReloadPreload = TIM_AUTORELOAD_PRELOAD_DISABLE;
  sConfig.EncoderMode = TIM_ENCODERMODE_TI1;
  sConfig.IC1Polarity = TIM_ICPOLARITY_RISING;
  sConfig.IC1Selection = TIM_ICSELECTION_DIRECTTI;
  sConfig.IC1Prescaler = TIM_ICPSC_DIV1;
  sConfig.IC1Filter = 0;
  sConfig.IC2Polarity = TIM_ICPOLARITY_RISING;
  sConfig.IC2Selection = TIM_ICSELECTION_DIRECTTI;
  sConfig.IC2Prescaler = TIM_ICPSC_DIV1;
  sConfig.IC2Filter = 0;
  if (HAL_TIM_Encoder_Init(&htim1, &sConfig) != HAL_OK)
  {
    Error_Handler();
  }
  sMasterConfig.MasterOutputTrigger = TIM_TRGO_RESET;
  sMasterConfig.MasterOutputTrigger2 = TIM_TRGO2_RESET;
  sMasterConfig.MasterSlaveMode = TIM_MASTERSLAVEMODE_DISABLE;
  if (HAL_TIMEx_MasterConfigSynchronization(&htim1, &sMasterConfig) != HAL_OK)
  {
    Error_Handler();
  }

}

static void MX_TIM3_Init(void)
{

  TIM_Encoder_InitTypeDef sConfig = {0};
  TIM_MasterConfigTypeDef sMasterConfig = {0};

  htim3.Instance = TIM3;
  htim3.Init.Prescaler = 0;
  htim3.Init.CounterMode = TIM_COUNTERMODE_UP;
  htim3.Init.Period = 65535;
  htim3.Init.ClockDivision = TIM_CLOCKDIVISION_DIV1;
  htim3.Init.AutoReloadPreload = TIM_AUTORELOAD_PRELOAD_DISABLE;
  sConfig.EncoderMode = TIM_ENCODERMODE_TI1;
  sConfig.IC1Polarity = TIM_ICPOLARITY_RISING;
  sConfig.IC1Selection = TIM_ICSELECTION_DIRECTTI;
  sConfig.IC1Prescaler = TIM_ICPSC_DIV1;
  sConfig.IC1Filter = 0;
  sConfig.IC2Polarity = TIM_ICPOLARITY_RISING;
  sConfig.IC2Selection = TIM_ICSELECTION_DIRECTTI;
  sConfig.IC2Prescaler = TIM_ICPSC_DIV1;
  sConfig.IC2Filter = 0;
  if (HAL_TIM_Encoder_Init(&htim3, &sConfig) != HAL_OK)
  {
    Error_Handler();
  }
  sMasterConfig.MasterOutputTrigger = TIM_TRGO_RESET;
  sMasterConfig.MasterSlaveMode = TIM_MASTERSLAVEMODE_DISABLE;
  if (HAL_TIMEx_MasterConfigSynchronization(&htim3, &sMasterConfig) != HAL_OK)
  {
    Error_Handler();
  }

}

static void MX_TIM4_Init(void)
{

  TIM_Encoder_InitTypeDef sConfig = {0};
  TIM_MasterConfigTypeDef sMasterConfig = {0};

  htim4.Instance = TIM4;
  htim4.Init.Prescaler = 0;
  htim4.Init.CounterMode = TIM_COUNTERMODE_UP;
  htim4.Init.Period = 65535;
  htim4.Init.ClockDivision = TIM_CLOCKDIVISION_DIV1;
  htim4.Init.AutoReloadPreload = TIM_AUTORELOAD_PRELOAD_DISABLE;
  sConfig.EncoderMode = TIM_ENCODERMODE_TI1;
  sConfig.IC1Polarity = TIM_ICPOLARITY_RISING;
  sConfig.IC1Selection = TIM_ICSELECTION_DIRECTTI;
  sConfig.IC1Prescaler = TIM_ICPSC_DIV1;
  sConfig.IC1Filter = 0;
  sConfig.IC2Polarity = TIM_ICPOLARITY_RISING;
  sConfig.IC2Selection = TIM_ICSELECTION_DIRECTTI;
  sConfig.IC2Prescaler = TIM_ICPSC_DIV1;
  sConfig.IC2Filter = 0;
  if (HAL_TIM_Encoder_Init(&htim4, &sConfig) != HAL_OK)
  {
    Error_Handler();
  }
  sMasterConfig.MasterOutputTrigger = TIM_TRGO_RESET;
  sMasterConfig.MasterSlaveMode = TIM_MASTERSLAVEMODE_DISABLE;
  if (HAL_TIMEx_MasterConfigSynchronization(&htim4, &sMasterConfig) != HAL_OK)
  {
    Error_Handler();
  }

}

static void MX_TIM6_Init(void)
{

  TIM_MasterConfigTypeDef sMasterConfig = {0};

  htim6.Instance = TIM6;
  htim6.Init.Prescaler = 0;
  htim6.Init.CounterMode = TIM_COUNTERMODE_UP;
  htim6.Init.Period = 180;
  htim6.Init.AutoReloadPreload = TIM_AUTORELOAD_PRELOAD_DISABLE;
  if (HAL_TIM_Base_Init(&htim6) != HAL_OK)
  {
    Error_Handler();
  }
  sMasterConfig.MasterOutputTrigger = TIM_TRGO_UPDATE;
  sMasterConfig.MasterSlaveMode = TIM_MASTERSLAVEMODE_DISABLE;
  if (HAL_TIMEx_MasterConfigSynchronization(&htim6, &sMasterConfig) != HAL_OK)
  {
    Error_Handler();
  }

}

static void MX_TIM8_Init(void)
{

  TIM_ClockConfigTypeDef sClockSourceConfig = {0};
  TIM_MasterConfigTypeDef sMasterConfig = {0};
  TIM_OC_InitTypeDef sConfigOC = {0};
  TIM_BreakDeadTimeConfigTypeDef sBreakDeadTimeConfig = {0};

  htim8.Instance = TIM8;
  htim8.Init.Prescaler = 180-1;
  htim8.Init.CounterMode = TIM_COUNTERMODE_UP;
  htim8.Init.Period = 999;
  htim8.Init.ClockDivision = TIM_CLOCKDIVISION_DIV1;
  htim8.Init.RepetitionCounter = 0;
  htim8.Init.AutoReloadPreload = TIM_AUTORELOAD_PRELOAD_DISABLE;
  if (HAL_TIM_Base_Init(&htim8) != HAL_OK)
  {
    Error_Handler();
  }
  sClockSourceConfig.ClockSource = TIM_CLOCKSOURCE_INTERNAL;
  if (HAL_TIM_ConfigClockSource(&htim8, &sClockSourceConfig) != HAL_OK)
  {
    Error_Handler();
  }
  if (HAL_TIM_PWM_Init(&htim8) != HAL_OK)
  {
    Error_Handler();
  }
  sMasterConfig.MasterOutputTrigger = TIM_TRGO_RESET;
  sMasterConfig.MasterOutputTrigger2 = TIM_TRGO2_RESET;
  sMasterConfig.MasterSlaveMode = TIM_MASTERSLAVEMODE_DISABLE;
  if (HAL_TIMEx_MasterConfigSynchronization(&htim8, &sMasterConfig) != HAL_OK)
  {
    Error_Handler();
  }
  sConfigOC.OCMode = TIM_OCMODE_PWM1;
  sConfigOC.Pulse = 500;
  sConfigOC.OCPolarity = TIM_OCPOLARITY_HIGH;
  sConfigOC.OCNPolarity = TIM_OCNPOLARITY_HIGH;
  sConfigOC.OCFastMode = TIM_OCFAST_DISABLE;
  sConfigOC.OCIdleState = TIM_OCIDLESTATE_RESET;
  sConfigOC.OCNIdleState = TIM_OCNIDLESTATE_RESET;
  if (HAL_TIM_PWM_ConfigChannel(&htim8, &sConfigOC, TIM_CHANNEL_1) != HAL_OK)
  {
    Error_Handler();
  }
  sBreakDeadTimeConfig.OffStateRunMode = TIM_OSSR_DISABLE;
  sBreakDeadTimeConfig.OffStateIDLEMode = TIM_OSSI_DISABLE;
  sBreakDeadTimeConfig.LockLevel = TIM_LOCKLEVEL_OFF;
  sBreakDeadTimeConfig.DeadTime = 0;
  sBreakDeadTimeConfig.BreakState = TIM_BREAK_DISABLE;
  sBreakDeadTimeConfig.BreakPolarity = TIM_BREAKPOLARITY_HIGH;
  sBreakDeadTimeConfig.BreakFilter = 0;
  sBreakDeadTimeConfig.BreakAFMode = TIM_BREAK_AFMODE_INPUT;
  sBreakDeadTimeConfig.Break2State = TIM_BREAK2_DISABLE;
  sBreakDeadTimeConfig.Break2Polarity = TIM_BREAK2POLARITY_HIGH;
  sBreakDeadTimeConfig.Break2Filter = 0;
  sBreakDeadTimeConfig.Break2AFMode = TIM_BREAK_AFMODE_INPUT;
  sBreakDeadTimeConfig.AutomaticOutput = TIM_AUTOMATICOUTPUT_DISABLE;
  if (HAL_TIMEx_ConfigBreakDeadTime(&htim8, &sBreakDeadTimeConfig) != HAL_OK)
  {
    Error_Handler();
  }
  HAL_TIM_MspPostInit(&htim8);

}

static void MX_TIM20_Init(void)
{

  TIM_MasterConfigTypeDef sMasterConfig = {0};
  TIM_OC_InitTypeDef sConfigOC = {0};
  TIM_BreakDeadTimeConfigTypeDef sBreakDeadTimeConfig = {0};

  htim20.Instance = TIM20;
  htim20.Init.Prescaler = 0;
  htim20.Init.CounterMode = TIM_COUNTERMODE_UP;
  htim20.Init.Period = 179;
  htim20.Init.ClockDivision = TIM_CLOCKDIVISION_DIV1;
  htim20.Init.RepetitionCounter = 0;
  htim20.Init.AutoReloadPreload = TIM_AUTORELOAD_PRELOAD_DISABLE;
  if (HAL_TIM_PWM_Init(&htim20) != HAL_OK)
  {
    Error_Handler();
  }
  sMasterConfig.MasterOutputTrigger = TIM_TRGO_RESET;
  sMasterConfig.MasterOutputTrigger2 = TIM_TRGO2_RESET;
  sMasterConfig.MasterSlaveMode = TIM_MASTERSLAVEMODE_DISABLE;
  if (HAL_TIMEx_MasterConfigSynchronization(&htim20, &sMasterConfig) != HAL_OK)
  {
    Error_Handler();
  }
  sConfigOC.OCMode = TIM_OCMODE_PWM1;
  sConfigOC.Pulse = 0;
  sConfigOC.OCPolarity = TIM_OCPOLARITY_HIGH;
  sConfigOC.OCNPolarity = TIM_OCNPOLARITY_HIGH;
  sConfigOC.OCFastMode = TIM_OCFAST_DISABLE;
  sConfigOC.OCIdleState = TIM_OCIDLESTATE_RESET;
  sConfigOC.OCNIdleState = TIM_OCNIDLESTATE_RESET;
  if (HAL_TIM_PWM_ConfigChannel(&htim20, &sConfigOC, TIM_CHANNEL_3) != HAL_OK)
  {
    Error_Handler();
  }
  sBreakDeadTimeConfig.OffStateRunMode = TIM_OSSR_DISABLE;
  sBreakDeadTimeConfig.OffStateIDLEMode = TIM_OSSI_DISABLE;
  sBreakDeadTimeConfig.LockLevel = TIM_LOCKLEVEL_OFF;
  sBreakDeadTimeConfig.DeadTime = 0;
  sBreakDeadTimeConfig.BreakState = TIM_BREAK_DISABLE;
  sBreakDeadTimeConfig.BreakPolarity = TIM_BREAKPOLARITY_HIGH;
  sBreakDeadTimeConfig.BreakFilter = 0;
  sBreakDeadTimeConfig.BreakAFMode = TIM_BREAK_AFMODE_INPUT;
  sBreakDeadTimeConfig.Break2State = TIM_BREAK2_DISABLE;
  sBreakDeadTimeConfig.Break2Polarity = TIM_BREAK2POLARITY_HIGH;
  sBreakDeadTimeConfig.Break2Filter = 0;
  sBreakDeadTimeConfig.Break2AFMode = TIM_BREAK_AFMODE_INPUT;
  sBreakDeadTimeConfig.AutomaticOutput = TIM_AUTOMATICOUTPUT_DISABLE;
  if (HAL_TIMEx_ConfigBreakDeadTime(&htim20, &sBreakDeadTimeConfig) != HAL_OK)
  {
    Error_Handler();
  }
  HAL_TIM_MspPostInit(&htim20);

}

static void MX_DMA_Init(void)
{

  /* DMA controller clock enable */
  __HAL_RCC_DMAMUX1_CLK_ENABLE();
  __HAL_RCC_DMA1_CLK_ENABLE();
  __HAL_RCC_DMA2_CLK_ENABLE();

  /* DMA interrupt init */
  /* DMA1_Channel1_IRQn interrupt configuration */
  HAL_NVIC_SetPriority(DMA1_Channel1_IRQn, 0, 0);
  HAL_NVIC_EnableIRQ(DMA1_Channel1_IRQn);
  /* DMA1_Channel2_IRQn interrupt configuration */
  HAL_NVIC_SetPriority(DMA1_Channel2_IRQn, 0, 0);
  HAL_NVIC_EnableIRQ(DMA1_Channel2_IRQn);
  /* DMA1_Channel3_IRQn interrupt configuration */
  HAL_NVIC_SetPriority(DMA1_Channel3_IRQn, 0, 0);
  HAL_NVIC_EnableIRQ(DMA1_Channel3_IRQn);
  /* DMA1_Channel4_IRQn interrupt configuration */
  HAL_NVIC_SetPriority(DMA1_Channel4_IRQn, 0, 0);
  HAL_NVIC_EnableIRQ(DMA1_Channel4_IRQn);
  /* DMA1_Channel5_IRQn interrupt configuration */
  HAL_NVIC_SetPriority(DMA1_Channel5_IRQn, 0, 0);
  HAL_NVIC_EnableIRQ(DMA1_Channel5_IRQn);
  /* DMA1_Channel6_IRQn interrupt configuration */
  HAL_NVIC_SetPriority(DMA1_Channel6_IRQn, 0, 0);
  HAL_NVIC_EnableIRQ(DMA1_Channel6_IRQn);
  /* DMA1_Channel7_IRQn interrupt configuration */
  HAL_NVIC_SetPriority(DMA1_Channel7_IRQn, 0, 0);
  HAL_NVIC_EnableIRQ(DMA1_Channel7_IRQn);
  /* DMA2_Channel1_IRQn interrupt configuration */
  HAL_NVIC_SetPriority(DMA2_Channel1_IRQn, 0, 0);
  HAL_NVIC_EnableIRQ(DMA2_Channel1_IRQn);
  /* DMA1_Channel8_IRQn interrupt configuration */
  HAL_NVIC_SetPriority(DMA1_Channel8_IRQn, 0, 0);
  HAL_NVIC_EnableIRQ(DMA1_Channel8_IRQn);

}

static void MX_GPIO_Init(void)
{
  GPIO_InitTypeDef GPIO_InitStruct = {0};

  /* GPIO Ports Clock Enable */
  __HAL_RCC_GPIOC_CLK_ENABLE();
  __HAL_RCC_GPIOF_CLK_ENABLE();
  __HAL_RCC_GPIOA_CLK_ENABLE();
  __HAL_RCC_GPIOB_CLK_ENABLE();
  __HAL_RCC_GPIOD_CLK_ENABLE();

  /*Configure GPIO pin Output Level */
  HAL_GPIO_WritePin(GPIOC, GPIO_PIN_13|GPIO_PIN_14|GPIO_PIN_15|LED_ONBARD_Pin
                          |ST7789_DC_Pin, GPIO_PIN_RESET);

  /*Configure GPIO pin Output Level */
  HAL_GPIO_WritePin(GPIOA, GPIO_PIN_2, GPIO_PIN_RESET);

  /*Configure GPIO pin Output Level */
  HAL_GPIO_WritePin(GPIOB, GPIO_PIN_14|GPIO_PIN_15|TLC5952_SCLK_Pin|TLC5952_LAT_Pin
                          |TLC5952_SIN_Pin, GPIO_PIN_RESET);

  /*Configure GPIO pin Output Level */
  HAL_GPIO_WritePin(FT6336_RST_GPIO_Port, FT6336_RST_Pin, GPIO_PIN_RESET);

  /*Configure GPIO pins : PC13 PC14 PC15 LED_ONBARD_Pin
                           ST7789_DC_Pin */
  GPIO_InitStruct.Pin = GPIO_PIN_13|GPIO_PIN_14|GPIO_PIN_15|LED_ONBARD_Pin
                          |ST7789_DC_Pin;
  GPIO_InitStruct.Mode = GPIO_MODE_OUTPUT_PP;
  GPIO_InitStruct.Pull = GPIO_NOPULL;
  GPIO_InitStruct.Speed = GPIO_SPEED_FREQ_LOW;
  HAL_GPIO_Init(GPIOC, &GPIO_InitStruct);

  /*Configure GPIO pin : PA2 */
  GPIO_InitStruct.Pin = GPIO_PIN_2;
  GPIO_InitStruct.Mode = GPIO_MODE_OUTPUT_PP;
  GPIO_InitStruct.Pull = GPIO_NOPULL;
  GPIO_InitStruct.Speed = GPIO_SPEED_FREQ_LOW;
  HAL_GPIO_Init(GPIOA, &GPIO_InitStruct);

  /*Configure GPIO pin : PA3 */
  GPIO_InitStruct.Pin = GPIO_PIN_3;
  GPIO_InitStruct.Mode = GPIO_MODE_IT_RISING;
  GPIO_InitStruct.Pull = GPIO_NOPULL;
  HAL_GPIO_Init(GPIOA, &GPIO_InitStruct);

  /*Configure GPIO pins : PA4 PA5 PA6 PA7 */
  GPIO_InitStruct.Pin = GPIO_PIN_4|GPIO_PIN_5|GPIO_PIN_6|GPIO_PIN_7;
  GPIO_InitStruct.Mode = GPIO_MODE_ANALOG;
  GPIO_InitStruct.Pull = GPIO_NOPULL;
  HAL_GPIO_Init(GPIOA, &GPIO_InitStruct);

  /*Configure GPIO pin : PC4 */
  GPIO_InitStruct.Pin = GPIO_PIN_4;
  GPIO_InitStruct.Mode = GPIO_MODE_IT_RISING;
  GPIO_InitStruct.Pull = GPIO_NOPULL;
  HAL_GPIO_Init(GPIOC, &GPIO_InitStruct);

  /*Configure GPIO pins : PB0 PB1 PB2 PB8 */
  GPIO_InitStruct.Pin = GPIO_PIN_0|GPIO_PIN_1|GPIO_PIN_2|GPIO_PIN_8;
  GPIO_InitStruct.Mode = GPIO_MODE_IT_RISING;
  GPIO_InitStruct.Pull = GPIO_NOPULL;
  HAL_GPIO_Init(GPIOB, &GPIO_InitStruct);

  /*Configure GPIO pins : PB14 PB15 TLC5952_SCLK_Pin TLC5952_LAT_Pin
                           TLC5952_SIN_Pin */
  GPIO_InitStruct.Pin = GPIO_PIN_14|GPIO_PIN_15|TLC5952_SCLK_Pin|TLC5952_LAT_Pin
                          |TLC5952_SIN_Pin;
  GPIO_InitStruct.Mode = GPIO_MODE_OUTPUT_PP;
  GPIO_InitStruct.Pull = GPIO_NOPULL;
  GPIO_InitStruct.Speed = GPIO_SPEED_FREQ_LOW;
  HAL_GPIO_Init(GPIOB, &GPIO_InitStruct);

  /*Configure GPIO pin : FT6336_RST_Pin */
  GPIO_InitStruct.Pin = FT6336_RST_Pin;
  GPIO_InitStruct.Mode = GPIO_MODE_OUTPUT_PP;
  GPIO_InitStruct.Pull = GPIO_NOPULL;
  GPIO_InitStruct.Speed = GPIO_SPEED_FREQ_LOW;
  HAL_GPIO_Init(FT6336_RST_GPIO_Port, &GPIO_InitStruct);

}

/* USER CODE BEGIN 4 */

// 不定长数据接收完成回调函数
void HAL_UARTEx_RxEventCallback(UART_HandleTypeDef *huart, uint16_t Size)
{
  if (huart->Instance == USART1)
  {
    // 使用DMA将接收到的数据发送回去
    HAL_UART_Transmit_DMA(&huart1, BLE_rx_data, Size);
    HAL_UART_Transmit_DMA(&hlpuart1, BLE_rx_data, Size);

    // 重新启动接收，使用Ex函数，接收不定长数据
    HAL_UARTEx_ReceiveToIdle_DMA(&huart1, BLE_rx_data, sizeof(BLE_rx_data));
    // 关闭DMA传输过半中断（HAL库默认开启，但我们只需要接收完成中断）
    __HAL_DMA_DISABLE_IT(huart1.hdmarx, DMA_IT_HT);
  }
}

void HAL_ADC_ConvHalfCpltCallback	(ADC_HandleTypeDef *hadc)
{
    if (!LOCK_CH1 ) {
        for (size_t i = 0; i < 4096; i++) {
            BUFFER_ADC1_proc[i] = BUFFER_ADC1[i];

            // BUFFER_DPO_CH2_PROC[i] = BUFFER_DPO_CH2[i];
        }
        LOCK_CH1 =1;

    }
}

/* USER CODE END 4 */

void Error_Handler(void)
{
  __disable_irq();
  while (1)
  {
  }
}
